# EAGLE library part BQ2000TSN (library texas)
CHARGE MANAGEMENT IC

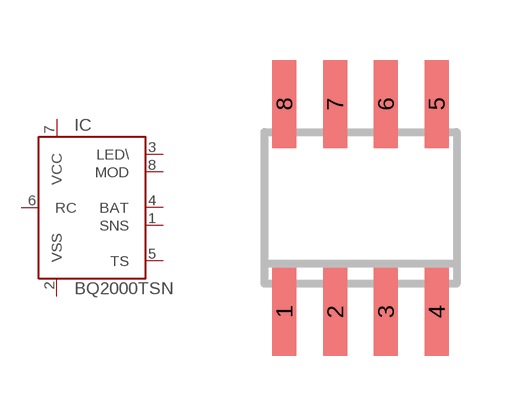
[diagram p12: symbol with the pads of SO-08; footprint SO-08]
Designator prefix IC

## BQ2000TSN  [SO-08]
1  SNS  in
2  VSS  pwr
3  LED\  out
4  BAT  in
5  TS  in
6  RC  in
7  VCC  in
8  MOD  out

## Footprint SO-08 (pad centres in mm)
Small Outline Integrated Circuit
smd 0.6 x 2.2: 1 -1.905,-2.6; 2 -0.635,-2.6; 3 0.635,-2.6; 4 1.905,-2.6; 5 1.905,2.6; 6 0.635,2.6; 7 -0.635,2.6; 8 -1.905,2.6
